VERSION 5.7 ;
  NOWIREEXTENSIONATPIN ON ;
  DIVIDERCHAR "/" ;
  BUSBITCHARS "[]" ;
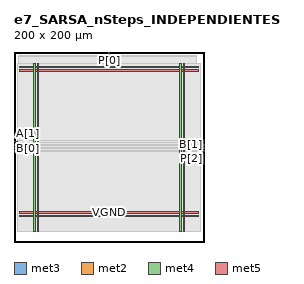
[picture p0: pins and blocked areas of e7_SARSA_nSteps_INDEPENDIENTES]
MACRO e7_SARSA_nSteps_INDEPENDIENTES
  CLASS BLOCK ;
  FOREIGN e7_SARSA_nSteps_INDEPENDIENTES ;
  ORIGIN 0.000 0.000 ;
  SIZE 200.000 BY 200.000 ;
  PIN A[0]
    DIRECTION INPUT ;
    USE SIGNAL ;
    ANTENNAGATEAREA 0.196500 ;
    PORT
      LAYER met3 ;
        RECT 0.000 95.240 4.000 95.840 ;
    END
  END A[0]
  PIN A[1]
    DIRECTION INPUT ;
    USE SIGNAL ;
    ANTENNAGATEAREA 0.213000 ;
    PORT
      LAYER met3 ;
        RECT 0.000 105.440 4.000 106.040 ;
    END
  END A[1]
  PIN B[0]
    DIRECTION INPUT ;
    USE SIGNAL ;
    ANTENNAGATEAREA 0.196500 ;
    PORT
      LAYER met3 ;
        RECT 0.000 98.640 4.000 99.240 ;
    END
  END B[0]
  PIN B[1]
    DIRECTION INPUT ;
    USE SIGNAL ;
    ANTENNAGATEAREA 0.213000 ;
    PORT
      LAYER met3 ;
        RECT 196.000 102.040 200.000 102.640 ;
    END
  END B[1]
  PIN P[0]
    DIRECTION OUTPUT ;
    USE SIGNAL ;
    ANTENNADIFFAREA 0.445500 ;
    PORT
      LAYER met2 ;
        RECT 99.910 196.000 100.190 200.000 ;
    END
  END P[0]
  PIN P[1]
    DIRECTION OUTPUT ;
    USE SIGNAL ;
    ANTENNADIFFAREA 0.445500 ;
    PORT
      LAYER met3 ;
        RECT 0.000 102.040 4.000 102.640 ;
    END
  END P[1]
  PIN P[2]
    DIRECTION OUTPUT ;
    USE SIGNAL ;
    ANTENNADIFFAREA 0.445500 ;
    PORT
      LAYER met3 ;
        RECT 196.000 95.240 200.000 95.840 ;
    END
  END P[2]
  PIN P[3]
    DIRECTION OUTPUT ;
    USE SIGNAL ;
    ANTENNADIFFAREA 0.445500 ;
    PORT
      LAYER met3 ;
        RECT 196.000 98.640 200.000 99.240 ;
    END
  END P[3]
  PIN VGND
    DIRECTION INOUT ;
    USE GROUND ;
    PORT
      LAYER met4 ;
        RECT 24.340 10.640 25.940 187.920 ;
    END
    PORT
      LAYER met4 ;
        RECT 177.940 10.640 179.540 187.920 ;
    END
    PORT
      LAYER met5 ;
        RECT 5.280 30.030 194.360 31.630 ;
    END
    PORT
      LAYER met5 ;
        RECT 5.280 183.210 194.360 184.810 ;
    END
  END VGND
  PIN VPWR
    DIRECTION INOUT ;
    USE POWER ;
    PORT
      LAYER met4 ;
        RECT 21.040 10.640 22.640 187.920 ;
    END
    PORT
      LAYER met4 ;
        RECT 174.640 10.640 176.240 187.920 ;
    END
    PORT
      LAYER met5 ;
        RECT 5.280 26.730 194.360 28.330 ;
    END
    PORT
      LAYER met5 ;
        RECT 5.280 179.910 194.360 181.510 ;
    END
  END VPWR
  OBS
      LAYER nwell ;
        RECT 5.330 10.795 194.310 187.870 ;
      LAYER li1 ;
        RECT 5.520 10.795 194.120 187.765 ;
      LAYER met1 ;
        RECT 4.210 10.640 194.120 187.920 ;
      LAYER met2 ;
        RECT 4.230 195.720 99.630 196.000 ;
        RECT 100.470 195.720 192.190 196.000 ;
        RECT 4.230 10.695 192.190 195.720 ;
      LAYER met3 ;
        RECT 3.990 106.440 196.000 187.845 ;
        RECT 4.400 105.040 196.000 106.440 ;
        RECT 3.990 103.040 196.000 105.040 ;
        RECT 4.400 101.640 195.600 103.040 ;
        RECT 3.990 99.640 196.000 101.640 ;
        RECT 4.400 98.240 195.600 99.640 ;
        RECT 3.990 96.240 196.000 98.240 ;
        RECT 4.400 94.840 195.600 96.240 ;
        RECT 3.990 10.715 196.000 94.840 ;
  END
END e7_SARSA_nSteps_INDEPENDIENTES
END LIBRARY

